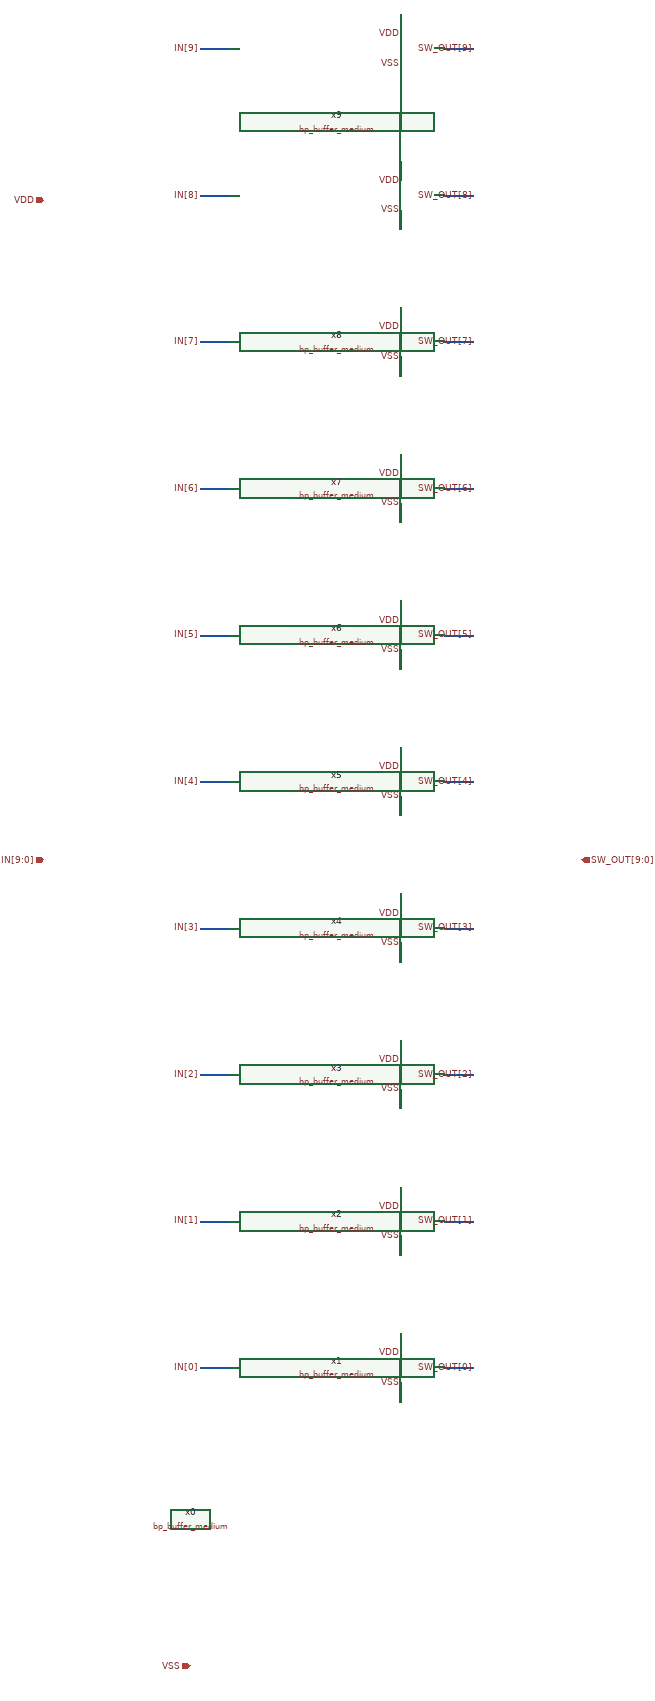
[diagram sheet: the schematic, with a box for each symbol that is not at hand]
v {xschem version=3.4.8RC file_version=1.3}
G {}
K {}
V {}
S {}
F {}
E {}
N 530 -380 530 -340 {lab=VDD}
N 180 -310 120 -310 {lab=IN[0]}
N 620 -310 680 -310 {lab=SW_OUT[0]}
N 530 -240 530 -280 {lab=VSS}
N 530 -680 530 -640 {lab=VDD}
N 180 -610 120 -610 {lab=IN[1]}
N 620 -610 680 -610 {lab=SW_OUT[1]}
N 530 -540 530 -580 {lab=VSS}
N 530 -980 530 -940 {lab=VDD}
N 180 -910 120 -910 {lab=IN[2]}
N 620 -910 680 -910 {lab=SW_OUT[2]}
N 530 -840 530 -880 {lab=VSS}
N 530 -1280 530 -1240 {lab=VDD}
N 180 -1210 120 -1210 {lab=IN[3]}
N 620 -1210 680 -1210 {lab=SW_OUT[3]}
N 530 -1140 530 -1180 {lab=VSS}
N 530 -1580 530 -1540 {lab=VDD}
N 180 -1510 120 -1510 {lab=IN[4]}
N 620 -1510 680 -1510 {lab=SW_OUT[4]}
N 530 -1440 530 -1480 {lab=VSS}
N 530 -1880 530 -1840 {lab=VDD}
N 180 -1810 120 -1810 {lab=IN[5]}
N 620 -1810 680 -1810 {lab=SW_OUT[5]}
N 530 -1740 530 -1780 {lab=VSS}
N 530 -2180 530 -2140 {lab=VDD}
N 180 -2110 120 -2110 {lab=IN[6]}
N 620 -2110 680 -2110 {lab=SW_OUT[6]}
N 530 -2040 530 -2080 {lab=VSS}
N 530 -2480 530 -2440 {lab=VDD}
N 180 -2410 120 -2410 {lab=IN[7]}
N 620 -2410 680 -2410 {lab=SW_OUT[7]}
N 530 -2340 530 -2380 {lab=VSS}
N 530 -2780 530 -2740 {lab=VDD}
N 180 -2710 120 -2710 {lab=IN[8]}
N 620 -2710 680 -2710 {lab=SW_OUT[8]}
N 530 -2640 530 -2680 {lab=VSS}
N 530 -3080 530 -3040 {lab=VDD}
N 180 -3010 120 -3010 {lab=IN[9]}
N 620 -3010 680 -3010 {lab=SW_OUT[9]}
N 530 -2940 530 -2980 {lab=VSS}
C {bp_buffer_medium.sym} 100 0 0 0 {name=x0}
C {bp_buffer_medium.sym} 100 -300 0 0 {name=x1}
C {bp_buffer_medium.sym} 100 -600 0 0 {name=x2}
C {bp_buffer_medium.sym} 100 -900 0 0 {name=x3}
C {bp_buffer_medium.sym} 100 -1200 0 0 {name=x4}
C {bp_buffer_medium.sym} 100 -1500 0 0 {name=x5}
C {bp_buffer_medium.sym} 100 -1800 0 0 {name=x6}
C {bp_buffer_medium.sym} 100 -2100 0 0 {name=x7}
C {bp_buffer_medium.sym} 100 -2400 0 0 {name=x8}
C {bp_buffer_medium.sym} 100 -2700 0 0 {name=x9}
C {lab_wire.sym} 530 -340 0 0 {name=p1 sig_type=std_logic lab=VDD}
C {lab_wire.sym} 120 -310 0 0 {name=p2 sig_type=std_logic lab=IN[0]}
C {lab_wire.sym} 680 -310 0 0 {name=p3 sig_type=std_logic lab=SW_OUT[0]}
C {lab_wire.sym} 530 -280 0 0 {name=p4 sig_type=std_logic lab=VSS}
C {lab_wire.sym} 530 -640 0 0 {name=p5 sig_type=std_logic lab=VDD}
C {lab_wire.sym} 120 -610 0 0 {name=p6 sig_type=std_logic lab=IN[1]}
C {lab_wire.sym} 680 -610 0 0 {name=p7 sig_type=std_logic lab=SW_OUT[1]}
C {lab_wire.sym} 530 -580 0 0 {name=p8 sig_type=std_logic lab=VSS}
C {lab_wire.sym} 530 -940 0 0 {name=p9 sig_type=std_logic lab=VDD}
C {lab_wire.sym} 120 -910 0 0 {name=p10 sig_type=std_logic lab=IN[2]}
C {lab_wire.sym} 680 -910 0 0 {name=p11 sig_type=std_logic lab=SW_OUT[2]}
C {lab_wire.sym} 530 -880 0 0 {name=p12 sig_type=std_logic lab=VSS}
C {lab_wire.sym} 530 -1240 0 0 {name=p13 sig_type=std_logic lab=VDD}
C {lab_wire.sym} 120 -1210 0 0 {name=p14 sig_type=std_logic lab=IN[3]}
C {lab_wire.sym} 680 -1210 0 0 {name=p15 sig_type=std_logic lab=SW_OUT[3]}
C {lab_wire.sym} 530 -1180 0 0 {name=p16 sig_type=std_logic lab=VSS}
C {lab_wire.sym} 530 -1540 0 0 {name=p17 sig_type=std_logic lab=VDD}
C {lab_wire.sym} 120 -1510 0 0 {name=p18 sig_type=std_logic lab=IN[4]}
C {lab_wire.sym} 680 -1510 0 0 {name=p19 sig_type=std_logic lab=SW_OUT[4]}
C {lab_wire.sym} 530 -1480 0 0 {name=p20 sig_type=std_logic lab=VSS}
C {lab_wire.sym} 530 -1840 0 0 {name=p21 sig_type=std_logic lab=VDD}
C {lab_wire.sym} 120 -1810 0 0 {name=p22 sig_type=std_logic lab=IN[5]}
C {lab_wire.sym} 680 -1810 0 0 {name=p23 sig_type=std_logic lab=SW_OUT[5]}
C {lab_wire.sym} 530 -1780 0 0 {name=p24 sig_type=std_logic lab=VSS}
C {lab_wire.sym} 530 -2140 0 0 {name=p25 sig_type=std_logic lab=VDD}
C {lab_wire.sym} 120 -2110 0 0 {name=p26 sig_type=std_logic lab=IN[6]}
C {lab_wire.sym} 680 -2110 0 0 {name=p27 sig_type=std_logic lab=SW_OUT[6]}
C {lab_wire.sym} 530 -2080 0 0 {name=p28 sig_type=std_logic lab=VSS}
C {lab_wire.sym} 530 -2440 0 0 {name=p29 sig_type=std_logic lab=VDD}
C {lab_wire.sym} 120 -2410 0 0 {name=p30 sig_type=std_logic lab=IN[7]}
C {lab_wire.sym} 680 -2410 0 0 {name=p31 sig_type=std_logic lab=SW_OUT[7]}
C {lab_wire.sym} 530 -2380 0 0 {name=p32 sig_type=std_logic lab=VSS}
C {lab_wire.sym} 530 -2740 0 0 {name=p33 sig_type=std_logic lab=VDD}
C {lab_wire.sym} 120 -2710 0 0 {name=p34 sig_type=std_logic lab=IN[8]}
C {lab_wire.sym} 680 -2710 0 0 {name=p35 sig_type=std_logic lab=SW_OUT[8]}
C {lab_wire.sym} 530 -2680 0 0 {name=p36 sig_type=std_logic lab=VSS}
C {lab_wire.sym} 530 -3040 0 0 {name=p37 sig_type=std_logic lab=VDD}
C {lab_wire.sym} 120 -3010 0 0 {name=p38 sig_type=std_logic lab=IN[9]}
C {lab_wire.sym} 680 -3010 0 0 {name=p39 sig_type=std_logic lab=SW_OUT[9]}
C {lab_wire.sym} 530 -2980 0 0 {name=p40 sig_type=std_logic lab=VSS}
C {iopin.sym} -200 -2700 0 0 {name=pb1 lab=VDD}
C {opin.sym} 900 -1350 0 0 {name=pb2 lab=SW_OUT[9:0]}
C {ipin.sym} -200 -1350 0 0 {name=pb3 lab=IN[9:0]}
C {iopin.sym} 100 300 0 0 {name=pb4 lab=VSS}
